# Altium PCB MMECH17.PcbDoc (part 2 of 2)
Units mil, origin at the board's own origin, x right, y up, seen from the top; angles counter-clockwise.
Board outline 2559.06 x 2205.16 mil, 4 copper layers (Top Layer, Ground Plane, Mid Layer 1, Bottom Layer), stack 56.756 mil thick; 96 components, 80 nets, 346 pads, 621 vias.

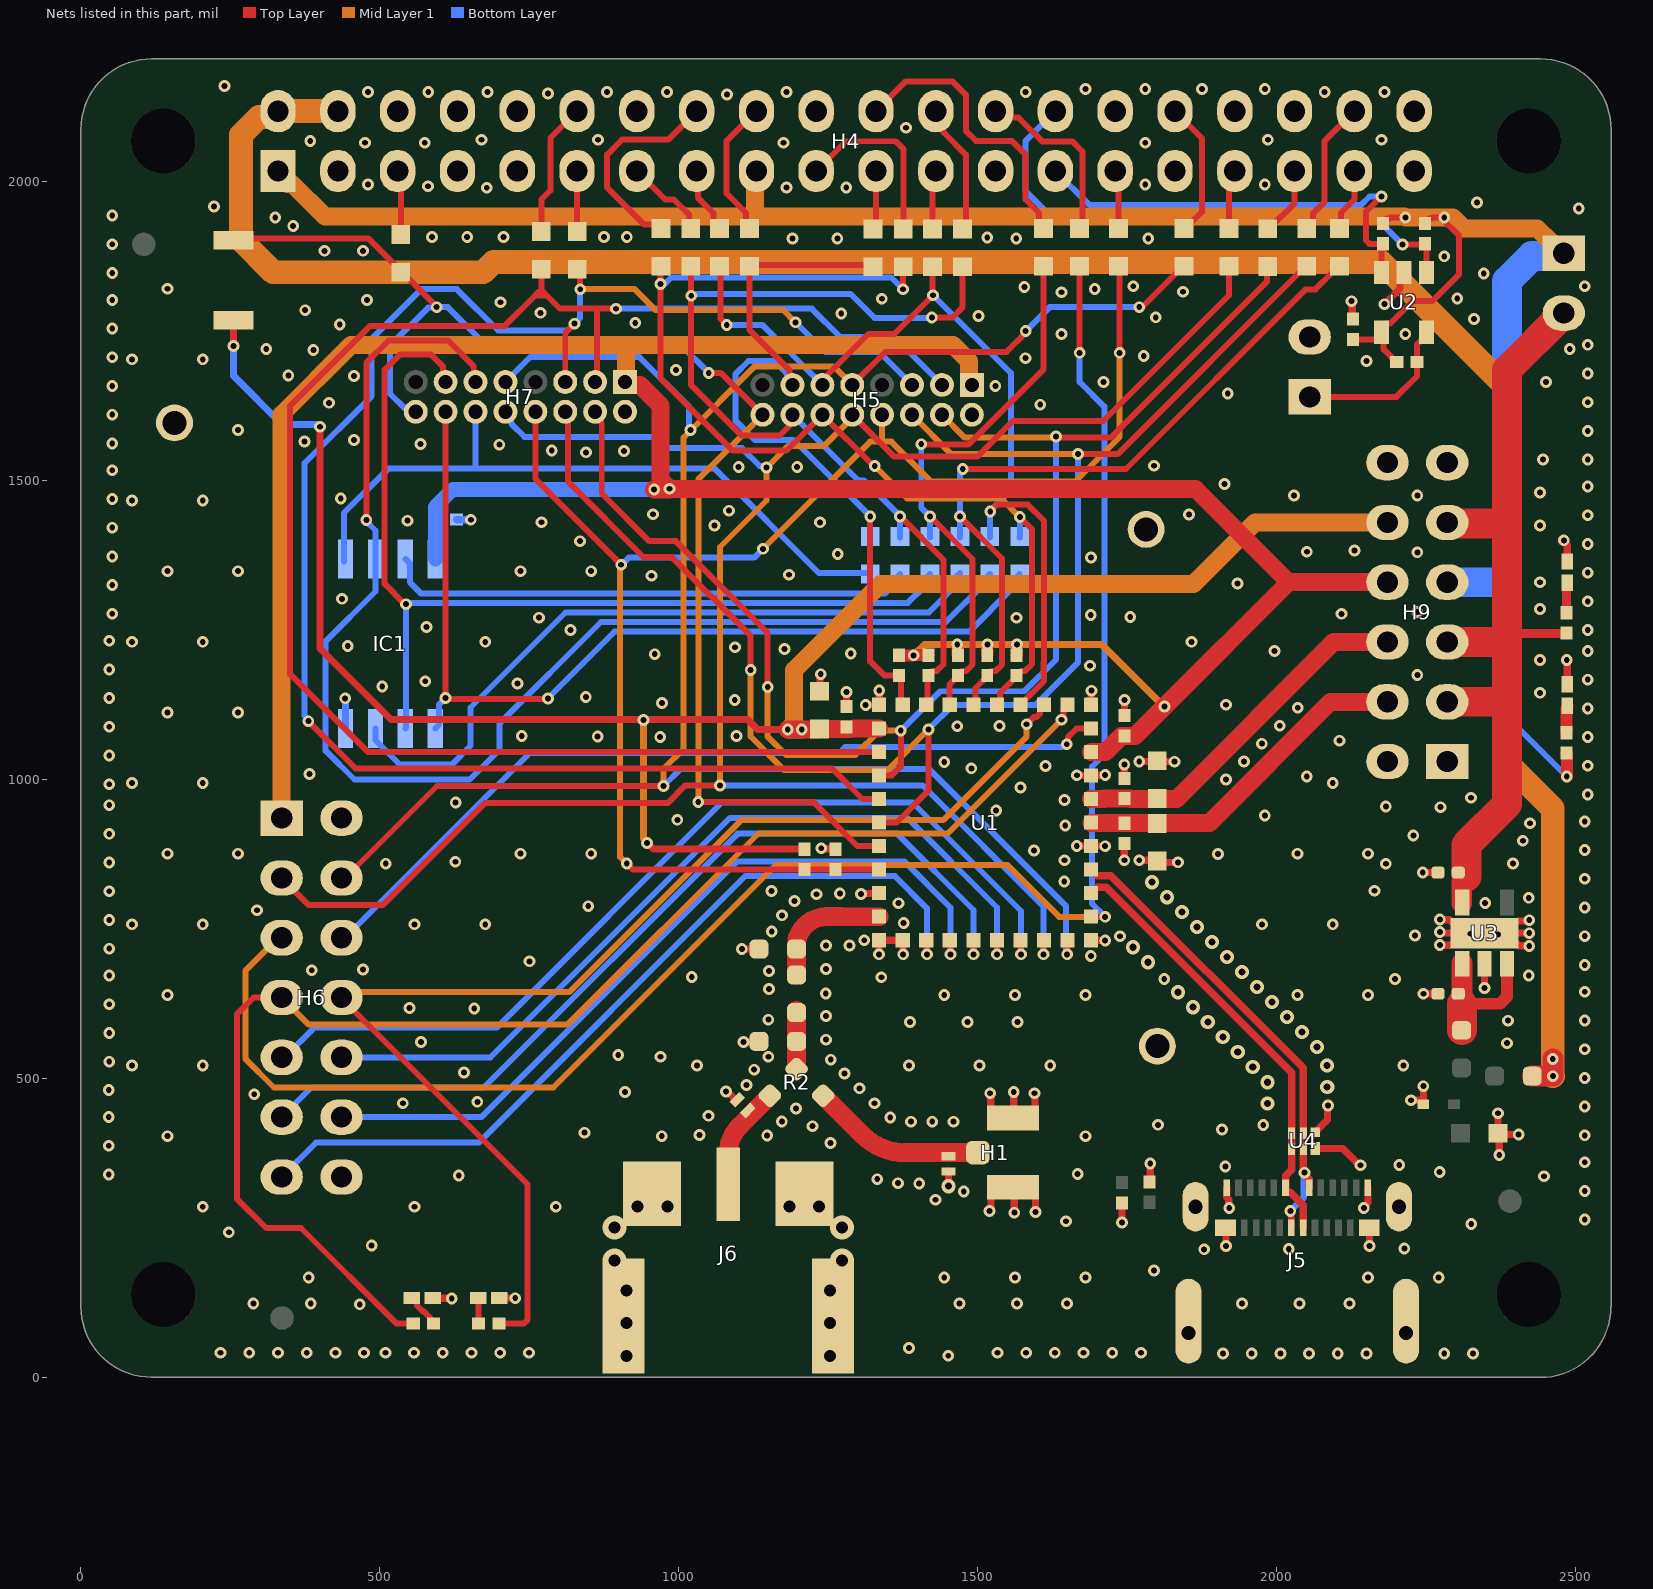
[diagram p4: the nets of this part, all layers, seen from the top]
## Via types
v1: diameter 19.68, hole 9.84, Top Layer to Bottom Layer, tented both sides, 584 vias
v2: diameter 23.62, hole 11.81, Top Layer to Bottom Layer, tented both sides, 25 vias
v3: diameter 40, hole 20, Top Layer to Bottom Layer, 12 vias

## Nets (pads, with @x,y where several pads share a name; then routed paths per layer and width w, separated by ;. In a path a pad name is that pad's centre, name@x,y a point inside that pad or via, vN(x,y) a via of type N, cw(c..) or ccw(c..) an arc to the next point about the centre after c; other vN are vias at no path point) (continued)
GND: C1.1 C2.2 C3.2 C4.2 C5.1 C6.2 C7.2 C8.2 C9.1 C10.2 C11.2 C12.2 C13.2 D1.1 D2.1 D3.K D4.K D5.K D6.K H1.2 H1.3 H3.2 H4.6 H4.9 H4.14 H4.20 H4.25 H4.30 H4.34 H4.39 H5.2 H6.2 H6.14 H7.2 H9.1 H9.2 H9.11 H9.12 IC1.4 J5.A1 J5.A12 J5.B1 J5.B12 J5.SH1 J5.SH2 J5.SH3 J5.SH4 J6.2 R3.1 R4.1 R45.2 R46.2 TP1.1 TP2.1 TP3.1 U1.1 U1.3 U1.11 U1.20 U1.23 U1.26 U1.30 U1.38 U2.2 U3.2 U3.6 U4.3 U4.4 VS1.A | length 1921.2
  Top Layer w12: D3.K@588.58,132.87 589.07,132.39 619.62,132.39 v1(620.11,131.9) ; D3.K@589.05,132.87 D3.K@589.17,132.76 ; D4.K@699.8,132.87 699.93,132.74 726.22,132.74 v1(726.35,132.61) ; v1(1078.74,478.35) 1080.82,478.35 1095.39,463.78 1096.65,463.78 D2.1@1097.44,464.57 ; v1(1105.32,716.54) R3.1@1133.86,716.54 ; v1(1108.27,561.02) 1108.76,561.52 1133.37,561.52 R4.1@1133.86,562.01 ; C4.2@1235.24,1147.64 1236.26,1148.66 1236.26,1175.24 v1(1237.28,1176.26) ; v1(1238.11,885) 1238.78,884.33 1261.05,884.33 C10.2@1261.72,883.66 ; C5.1@1279.53,1126.77 1279.97,1126.77 1280.2,1127 1280.2,1146.18 v1(1280.24,1146.22) ; v1(1304.51,808.73) 1305.15,809.37 1334.37,809.37 U1.3@1335,810 ; v1(1312.41,1124.59) 1312.49,1124.51 U1.11@1336.31,1124.51 ; v1(1334.86,707.64) 1334.93,707.71 1334.93,731.19 U1.1@1335,731.26 U1.38@1374.37,731.26 1374.76,730.86 1374.76,708.03 v1(1375.16,707.64) ; U1.11@1335,1124.96 U1.11@1335.08,1125.04 ; U1.11@1335,1125.12 U1.11@1335.08,1125.04 ; v1(1335.16,1148.94) 1335.08,1148.86 U1.11@1335.08,1125.04 ; U1.11@1336.23,1124.43 U1.11@1336.31,1124.51 ; U1.11@1336.39,1124.43 U1.11@1336.31,1124.51 ; D1.1@1449.8,345.47 D1.1@1450.79,344.49 v2(1450.79,319.88) ; v1(1519.68,278.54) 1521.91,280.77 1521.91,302.47 H1.3@1522.64,303.2 ; v1(1520.67,475.39) 1521.75,474.32 1521.75,448.72 1533.46,437.01 1559.06,437.01 H1.2@1559.06,434.06 ; H1.3@1558.07,312.99 1561.02,310.04 v1(1561.02,275.59) ; v1(1560.04,477.36) 1560.04,440.94 H1.2@1561.02,439.96 ; v1@1593.5,476.38 1595.73,474.15 1595.73,450.49 H1.2@1596.46,449.76 ; H1.3@1594.49,304.23 1595.38,304.23 1596.36,303.24 1596.36,276.67 v1(1596.46,276.57) ; v1(1665.49,888.87) 1665.57,888.79 U1.26@1689.38,888.79 ; v1(1665.57,1007.07) 1665.65,1006.99 U1.23@1689.47,1006.99 ; U1.30@1689.33,731.26 1689.48,731.11 1712.81,731.11 v1(1712.95,730.97) ; U1.26@1689.33,888.74 1689.4,888.67 1712.89,888.67 v1(1712.95,888.61) ; U1.23@1689.33,1006.85 U1.23@1689.47,1006.99 ; U1.20@1689.33,1124.96 1689.61,1125.24 1689.61,1148.31 v1(1689.88,1148.58) ; U1.23@1689.55,1006.91 U1.23@1689.47,1006.99 ; v1(1712.95,1007.39) 1712.68,1007.12 1689.6,1007.12 U1.23@1689.47,1006.99 ; v1(1741.14,259.06) R45.2@1741.14,291.73 ; v1(1745,865) C3.2@1745,892.68 ; C7.2@1745,1002.32 v1(1745,1025) ; C8.2@1745,1107 C8.2@1745,1107 1745.04,1132.83 v1(1745.08,1132.87) ; v1(1770,865) 1799.53,865 1800,865.47 1803.99,861.48 v1(1834.7,861.48) ; v1(1770,1030) 1799.53,1030 C6.2@1800,1029.53 ; R46.2@1788.39,325.39 v1(1788.39,358.07) ; C6.2@1799.92,1032.4 1800,1032.48 C6.2@1799.92,1032.56 ; C6.2@1804.92,1030.08 1805,1030 1828.82,1030 v1(1828.9,1029.92) ; J5.B12@1914.21,250.55 1915,249.76 v1(1915,220) ; J5.A1@1916.18,317.48 1916.18,300.92 1919.51,297.6 1919.51,284.31 v1(1920.55,283.26) ; U4.3@2063.98,382.78 2110.3,382.78 2138.18,354.9 v1(2140,354.9) ; U4.4@2064.29,410.14 2064.29,410.53 2084.65,430.89 2084.65,451.77 v1@2085.63,452.76 ; v1(2125,1800) 2126.25,1798.75 2126.25,1771.65 C9.1@2127.5,1770.4 ; v1(2145.55,283.26) 2145.55,285.34 2152.4,292.19 J5.A12@2152.4,317.48 ; J5.B1@2154.37,250.55 2155,249.92 v1(2155,220) ; v1(2180,1795) 2206,1821 2206,1841.58 U2.2@2212.5,1848.08 ; v1(2224.41,463.58) VS1.A@2245.08,463.58 ; v1@2244.18,844.46 C12.2@2269.38,844.46 ; 2245.08,466.54 v1(2245.08,487.2) ; v1(2245.08,641.73) C11.2@2269.42,641.73 ; v1(2272.64,723.43) 2273.14,722.93 2290.6,722.93 2294.05,726.38 U3.6@2294.29,726.38 ; v1(2272.64,745.08) 2274.11,743.61 2287.98,743.61 2288.48,743.11 U3.6@2294.29,743.11 ; v1(2272.64,765.75) 2272.97,765.42 2288.48,765.42 U3.6@2292.2,761.69 ; U3.2@2346.46,690.94 2347.44,689.96 v1(2347.44,651.57) ; C13.2@2370.08,411.42 v1(2370.08,441.93) ; v1(2372.05,372.05) C13.2@2372.05,402.56 ; C13.2@2374.02,406.5 v1(2404.53,406.5) ; U3.6@2398.62,743.11 v1(2422.24,743.11) ; U3.6@2402.68,724.53 2405.26,721.94 2421.76,721.94 v1(2422.24,721.46) ; U3.6@2403.3,762.31 2404.28,763.29 2420.77,763.29 v1(2422.24,764.76) ; v1(2480,1400) 2480,1397.92 2485.8,1392.12 D6.K@2485.8,1364.65 ; v1(2485,1200) 2485.8,1199.2 D5.K@2485.8,1158.98 ; v1(2490,1720) v1@2490.8,1719.2
  Bottom Layer w12: v1(441.93,1135.83) 442.29,1135.47 442.29,1085.98 IC1.4@442.65,1085.62 ; C1.1@628.54,1435.04 629.04,1434.55 v1(652.07,1434.55) v1@652.56,1434.06
  other v1: 1450.49,36.35 1910,40 1958,40 2006,40 2054,40 2102,40 2150,40 2280,40 2328,40 233.6,41.45 281.6,41.45 329.6,41.45 377.6,41.45 425.6,41.45 473.6,41.45 509.19,41.45 557.19,41.45 605.19,41.45 653.19,41.45 701.19,41.45 749.19,41.45 1532.81,41.45 1580.81,41.45 1628.81,41.45 1676.81,41.45 1724.81,41.45 1772.81,41.45 1384.84,49.21 466.32,122.31 288.35,123.93 384.35,123.93 1469.45,123.93 1565.45,123.93 1649.04,123.93 1941.89,123.93 2037.89,123.93 2121.49,123.93 380.91,167.32 1443.9,167.32 1562.01,167.32 1680.12,167.32 2152.56,167.32 2270.67,167.32 1794.76,179.13 1878.49,214.33 2020,215 2213.32,215.86 486.21,220.63 247.38,242.95 2325.18,256.62 1647.51,261.18 2515,264 203.74,285.43 558.07,285.43 794.29,285.43 1429.13,297.24 1476.38,311.02 2515,312 1401.92,324.19 1366.5,324.94 1331.7,331.62 2446.85,336.61 631.89,337.6 46.46,339.63 1666.96,340.27 2272.34,343.63 1913.9,353.05 2204.75,355.55 2515,360 46.46,387.63 1253.43,392.17 144.69,403.54 971.46,403.54 1680.12,403.54 1147.64,404.53 1034.57,405.42 2515,405 842.09,409.38 1908.32,414.75 1223.43,420.28 1801.25,422.5 1977.36,422.24 1388.25,427.78 1423.69,427.78 1459.12,427.78 1172.24,428.15 1353.49,434.66 46.46,435.63 1049.42,437.59 1195.87,449.8 2515,453 2085.63,454.72 538.39,458.66 1327.31,458.54 663,461.01 289.8,473.72 1594.62,475.27 909.97,477.26 46.46,480.63 1302.26,483.59 1113.19,489.17 2515,501 1277.1,508.54 640.75,509.84 1125.98,514.76 85.63,521.65 203.74,521.65 1030.51,521.65 1384.84,521.65 1502.95,521.65 1621.06,521.65 2211.61,521.65 47.33,528.18 1253.94,531.5 969.08,536.37 1149.61,536.42 898.6,539.53 2515,549 2384.84,559.06 568.9,561.02 1246.06,564.96 47.33,576.18 1386.78,594.4 1482.78,594.4 1566.37,594.4 2386.85,596.74 2515,597 1149.61,598.43 1246.06,604.33 549.47,617.84 657.85,617.14 47.33,624.18 144.69,639.76 1443.9,639.76 1562.01,639.76 1680.12,639.76 2034.45,639.76 2152.56,639.76 1245.72,642.2 2515,645 1150.59,649.61 1811.7,666.19 2197.83,666.34 1021.59,669.88 1338.58,669.29 47.33,672.18 2421.26,672.24 1150.71,679.83 385.98,681.07 471.8,682.22 1246.06,683.07 2515,690 750.2,695.95 1688.98,704.84 47.33,717.18 1246.06,722.44 1285.43,722.44 1310.04,731.3 1737.79,737.99 2515,738 2231.3,739.17 2370.08,741.14 2323.82,742.13 1155.29,745.69 85.63,757.87 203.74,757.87 558.07,757.87 676.18,757.87 1975.39,757.87 2093.5,757.87 1375.94,760.26 47.33,765.18 1172.55,772.92 294.4,781.29 2515,786 848.46,788.19 1367.46,793.2 2348.43,793.31 1193.26,796.69 2421.26,802.17 1230.32,808.07 1269.17,809.31 47.33,813.18 1155.14,813.36 2163.39,813.98 1644.58,829.59 2515,834 2244.15,844.42 509.84,859.25 2182.32,859.06 2394.96,859.46 47.33,861.18 626.16,862.5 1645.01,864.94 1901.78,875.42 144.69,875.98 262.8,875.98 735.24,875.98 853.35,875.98 2034.45,875.98 2152.56,875.98 1594.05,881.4 2515,882 2411.42,897.64 2228.35,906.5 47.33,909.18 1646.18,923.1 2423.47,926.82 2515,930 997.48,932.62 1980,940 1530.68,948.37 2273.62,953.74 2182.32,955.06 47.33,957.18 626.71,961.38 1644.98,965.62 2324.8,969.49 2520,975 1571.58,986.47 47.33,992.18 85.63,994.09 203.74,994.09 2093.5,994.09 1915,1000 2050,1005 382.44,1009.45 1489.17,1018.7 1613.19,1022.64 2520,1023 1443.9,1029.53 1945,1030 47.33,1040.18 1975,1060 2105,1065 864.17,1071.85 968.69,1071.22 2520,1071 737.2,1072.83 1096.46,1072.83 47.33,1088.18 1465.61,1089.04 1536.42,1089.57 2005,1090 144.69,1112.2 262.8,1112.2 2520,1119 2035,1120 1915,1125 971.77,1128.17 1093.5,1132.87 47.33,1136.18 844.4,1137.97 2440,1145 503.94,1155.51 730.04,1160.79 575.79,1164.37 2520,1167 2235,1175 47.33,1184.18 1687.51,1190.35 2440,1200 959.65,1209.65 1287.4,1210.63 1996.05,1214.77 2520,1215 1176.52,1218.3 1093.91,1221.27 446.3,1223.17 85.63,1230.31 203.74,1230.31 676.18,1230.31 1857.28,1230.31 47.33,1232.18 818.9,1250 2520,1250 577.76,1254.92 765.91,1270.69 1564.84,1270.6 1754.92,1271.65 1688.85,1275.1 52.33,1277.18 2108.16,1277.07 2235,1280 2440,1285 2520,1298 436.87,1302.2 52.33,1325.18 1934.06,1327.76 2440,1330 954.1,1340.74 1184.06,1342.52 2520,1346 144.69,1348.42 262.8,1348.42 735.24,1348.42 853.35,1348.42 1689.28,1371.26 52.33,1373.18 1265.75,1376.97 2050.2,1380.91 2235,1380 2129.92,1382.87 2520,1394 834.65,1398.67 52.33,1421.18 1059.69,1425 2440,1425 770.18,1430.2 1236.22,1430.12 546.04,1432.88 2520,1442 956.64,1443.64 1853.06,1443.31 1083.73,1449.65 85.63,1466.54 203.74,1466.54 52.33,1469.18 434.57,1469.95 2028.95,1475.12 2235,1475 2440,1480 2520,1490 1912.4,1494.09 52.33,1517.18 1100,1522.69 1197.83,1522.64 1794.54,1524.76 2445,1535 2520,1535 844.49,1547.24 908.46,1549.21 787.4,1550.2 699.8,1560.04 567.91,1561.02 52.33,1562.18 373.94,1565.5 456.51,1567.91 2520,1583 262.8,1584.65 52.33,1610.18 1604.33,1626.97 415,1630 2520,1631 1917.9,1645.76 52.33,1658.18 1529.3,1657.98 1710.14,1664.65 2450,1665 346.85,1675.52 456.51,1675 2520,1679 995,1685 2150,1700 85.63,1702.76 203.74,1702.76 1579.72,1704.72 52.33,1706.18 1777.43,1708.32 388.69,1718.29 310,1720 2520,1727 1639.76,1745.08 2215,1745 52.33,1754.18 432.86,1761.06 927.17,1763.78 2330,1770 1797.63,1772.95 1500.96,1775.05 1271.51,1779.42 768.7,1780.51 375,1785 701.77,1798.23 52.33,1802.18 478.42,1801.97 1339.45,1803.99 2301.83,1804.59 1640,1815 1842.92,1815.69 144.69,1820.87 1695.62,1820.34 1577.76,1823.82 1760,1825 2515,1825 2346.09,1846.25 52.33,1847.18 2280,1875 407.48,1884.16 471.84,1884.16 52.33,1895.18 1190,1905 1265,1905 1564.2,1905 1785,1905 1515.75,1906.5 586.94,1907.48 645.98,1907.48 706.66,1907.48 874.62,1907.48 912.98,1907.48 355,1925.84 325,1940 52.33,1943.18 2505,1955 222.36,1958.44 2335,1965 678.69,1989.65 1180,1990 1280,1990 580.32,1992.11 480,1995 1780,1995 1980,1995 475,2065 575,2065 1175,2065 1780,2065 383.52,2067.76 670,2070 865,2070 1985,2070 2175,2070 1380,2090 1080.33,2145.78 781.05,2147.49 480,2150 580.86,2150.02 680,2150 880,2150 980,2150 1180,2150 1580,2150 2080,2150 2180,2150 1680,2155 1780,2155 1875,2155 1980,2155 240,2160
  other v2: 1984.59,458.3 2084.31,486.06 1984.59,493.73 1959.78,519.03 2084.01,521.5 1934.72,544.08 2067.17,552.67 1909.67,569.14 2042.12,577.73 1884.62,594.19 2017.06,602.78 1859.56,619.24 1992.01,627.83 1834.51,644.3 1966.95,652.89 1941.9,677.94 1784.4,694.41 1916.84,703 1759.35,719.46 1891.79,728.05 1866.74,753.1 1841.68,778.16 1816.63,803.21 1791.57,828.27
  other v3: 912.68,35.83 1252.68,35.83 912.68,145.83 1252.68,145.83 892.68,195.83 1272.68,195.83 892.68,250.83 1272.68,250.83 930.68,285.83 980.68,285.83 1184.68,285.83 1234.68,285.83
LED_G: H6.7 R39.1 U1.19 | length 2339.5
  Top Layer w10: H6.7@335.8,635.41 288.95,635.41 260.83,607.28 260.83,299.21 310.04,250 368.11,250 527.56,90.55 R39.1@555.83,90.55 ; v1(1640,1100) 1640,1102.62 1643.15,1105.77 1643.15,1118.15 U1.19@1649.96,1124.96
  Mid Layer 1 w10: H6.7@335.8,635.41 381.2,590 813.43,590 1133.11,909.68 1449.68,909.68 v1(1640,1100)
LED_R: H6.8 R40.1 U1.18 | length 2105.7
  Top Layer w10: H6.8@440,630 747.19,322.81 747.19,96.6 741.14,90.55 R40.1@699.09,90.55 ; v1(1581.69,1092.52) 1593.5,1104.33 1597.92,1104.33 1603.78,1110.19 1603.78,1118.15 U1.18@1610.59,1124.96
  Mid Layer 1 w10: H6.8@435.8,635.41 445.18,644.79 471.88,644.79 472.09,645 817.24,645 1104.33,932.09 1442.09,932.09 1581.69,1071.69 v1(1581.69,1092.52)
MM_BUSY: H6.5 R29.1 U1.29 | length 3027.8
  Top Layer w10: R29.1@1670,1860.47 1670.28,1860.2 v1(1670.28,1713.58) ; U1.29@1689.33,770.63 1689.46,770.5 1712.83,770.5 v1(1712.95,770.38)
  Mid Layer 1 w10: H6.5@335.8,735.41 329.89,735.41 275,680.51 275,532.98 322.98,485 790.12,485 1162.4,857.28 1549.21,857.28 1636.12,770.38 v1(1712.95,770.38)
  Bottom Layer w10: v1(1670.28,1713.58) 1670.28,1664.81 1711.61,1623.47 1711.61,1042.32 1690.94,1021.65 1690.94,792.39 v1(1712.95,770.38)
MM_DBG_RX: H5.9 H6.4 H7.9 R30.1 U1.31 | length 3466.6
  Top Layer w10: H6.4@435.8,835.41 441.7,835.41 595.47,989.17 v1(974.41,989.17) ; H5.9@1290,1660 1345,1715 1547.62,1715 1580,1747.38 v1(1580,1750) ; v1(1649.36,707.64) 1649.66,707.94 1649.66,730.96 U1.31@1649.96,731.26 ; v1(1770,1790) 1771.85,1791.85 1776.38,1791.85 R30.1@1845,1860.47
  Mid Layer 1 w10: v1(974.41,989.17) 974.41,1017.72 1008.11,1051.41 1008.11,1571.95 1127.16,1691 1259,1691 H5.9@1290,1660
  Bottom Layer w10: H7.9@710,1665 751.69,1706.69 934.06,1706.69 1017.08,1623.67 1017.08,1587.25 v1(1019.68,1584.65) ; v1(974.41,989.17) 1002.61,1017.37 1418.65,1017.37 1647.84,788.18 1647.84,709.16 v1(1649.36,707.64) ; v1(1580,1750) 1620,1790 v1(1770,1790)
MM_DBG_TX: H5.10 H6.3 H7.10 R31.1 U1.32 | length 3612.9
  Top Layer w10: H6.3@335.8,835.41 381.2,790 505,790 675.63,960.63 981.3,960.63 1010.83,990.16 v1(1068.9,990.16) ; H5.10@1290,1610 1360,1540 1498.72,1540 1558.72,1600 1710.24,1600 1920,1809.76 R31.1@1920,1858.5 R31.1@1920,1860.47 ; v1(1609.62,707.64) 1610.1,708.13 1610.1,730.77 U1.32@1610.59,731.26
  Mid Layer 1 w10: v1(1068.9,990.16) 1068.9,1388.9 1146.65,1466.65 v1(1146.65,1521.65) 1183.07,1558.07 1243.11,1558.07 1290,1604.96 H5.10@1290,1610
  Bottom Layer w10: H7.10@710,1615 710,1606.88 719.73,1597.15 719.73,1595.23 741.95,1573.01 960.46,1573.01 979.33,1554.13 1105.31,1554.13 1135.19,1524.26 1144.05,1524.26 v1(1146.65,1521.65) ; v1(1068.9,990.16) 1407.48,990.16 1609.62,788.02 v1(1609.62,707.64)
MM_GPIO3: H6.6 U1.21 | length 1404.2
  Top Layer w10: v1(1648.62,1059.06) 1650.48,1060.91 1650.48,1070.48 1665.3,1085.3 1689.04,1085.3 U1.21@1689.33,1085.59
  Bottom Layer w10: H6.6@435.8,735.41 441.7,735.41 750.59,1044.29 1268.06,1044.29 1277.9,1054.13 1641.08,1054.13 1646,1059.06 v1(1648.62,1059.06)
MM_GPIO6: H6.9 U1.33 | length 1584.7
  Top Layer w10: U1.33@1571.22,731.26 1571.72,730.76 1571.72,708.13 v1(1572.21,707.64)
  Bottom Layer w10: H6.9@335.8,535.41 340.41,535.41 390,585 695.24,585 1071.85,961.61 1390.75,961.61 1572.21,780.15 v1(1572.21,707.64)
MM_GPIO7: H6.10 U1.34 | length 1426.3
  Top Layer w10: U1.34@1531.85,731.26 1531.94,731.17 1531.94,707.72 v1(1532.02,707.64)
  Bottom Layer w10: H6.10@435.8,535.41 685.01,535.41 1085.63,936.02 1381.89,936.02 1532.02,785.89 v1(1532.02,707.64)
MM_GPIO8: H6.11 U1.35 | length 1504.2
  Top Layer w10: U1.35@1492.48,731.26 1492.66,731.08 1492.66,707.82 v1(1492.84,707.64)
  Bottom Layer w10: H6.11@335.8,435.41 385.39,485 673.98,485 1098.43,909.45 1365.16,909.45 1492.84,781.77 v1(1492.84,707.64)
MM_GPIO9: H6.12 U1.36 | length 1331.5
  Top Layer w10: v1@1453.11,706.19 1453.71,706.79 1453.71,730.66 U1.36@1453.11,731.26
  Bottom Layer w10: H6.12@435.8,435.41 669.66,435.41 1097.44,863.19 1376.97,863.19 1454.32,785.84 v1(1454.32,707.64)
MM_GPIO10: H6.13 U1.37 | length 1411
  Top Layer w10: U1.37@1413.74,731.26 1414.27,730.73 1414.27,708.17 v1(1414.8,707.64)
  Bottom Layer w10: H6.13@335.8,335.41 393.11,392.72 665.35,392.72 1111.22,838.58 1361.22,838.58 1414.8,785.01 v1(1414.8,707.64)
MM_JTAG_TCK: H5.5 H7.5 R32.1 U1.7 | length 2928.2
  Top Layer w10: v1(380.37,1097.6) 459.26,1018.7 1255.91,1018.7 1307.13,967.48 U1.7@1335,967.48 ; H7.5@810,1665 810,1747.01 v1(825.36,1762.36) ; R32.1@830,1855.47 835,1850.47 v1(835,1820)
  Mid Layer 1 w10: v1(835,1820) 926.06,1820 960.63,1785.43 1174.06,1785.43 v1(1194.91,1764.59)
  Bottom Layer w10: v1(380.37,1097.6) 380.37,1100.22 374,1106.59 374,1529 486.22,1641.22 486.22,1737.2 569.02,1820 628.82,1820 697.83,1750.98 813.98,1750.98 v1(825.36,1762.36) 835,1772.01 v1(835,1820) ; v1(1194.91,1764.59) 1197.82,1761.68 1198.32,1761.68 1245,1715 1335,1715 H5.5@1390,1660
MM_JTAG_TDI: H5.3 H7.3 R34.1 U1.9 | length 2904
  Top Layer w10: R34.1@770,1855.47 R34.1@770,1853.5 770,1814.96 ; H7.3@860,1665 862.97,1667.97 862.97,1787.4 ; v1(894.68,1787.4) 862.97,1787.4 ; U1.9@1335,1046.22 479.86,1046.22 350,1176.08 350,1625 483.86,1758.86 708.86,1758.86 759.34,1809.34 ; 759.34,1809.34 777.09,1809.34 778.17,1810.41 ; 759.34,1809.34 764.96,1814.96 770,1814.96 ; 770,1814.96 773.62,1814.96 778.17,1810.41 ; 778.17,1810.41 801.18,1787.4 862.97,1787.4
  Bottom Layer w10: v1(894.68,1787.4) 1222.44,1787.4 1269.84,1740 1360,1740 H5.3@1440,1660
MM_JTAG_TDO: H5.4 H7.4 R35.1 U1.8 | length 2421
  Top Layer w10: H7.4@860,1615 860,1606.88 871.06,1595.82 871.06,1478.35 950.79,1398.62 995.08,1398.62 1148.62,1245.08 v1(1148.62,1154.53) ; U1.8@1335,1006.85 1356.26,1006.85 1371.18,1021.77 1371.18,1081.58 v1(1371.06,1081.69) ; v1(1630.91,1573.82) 1632.31,1572.41 1723,1572.41 1983.91,1833.32 1983.91,1859.13 R35.1@1984.96,1860.17
  Mid Layer 1 w10: v1(1148.62,1154.53) 1148.62,1071.85 1179.13,1041.34 1295.28,1041.34 1335.63,1081.69 v1(1371.06,1081.69) ; H5.4@1440,1610 1477.59,1572.41 1629.5,1572.41 v1(1630.91,1573.82)
  Bottom Layer w10: v1(1371.06,1081.69) 1437.01,1147.64 1577.76,1147.64 1630.91,1200.79 v1(1630.91,1573.82)
MM_JTAG_TMS: H5.6 H7.6 R33.1 U1.6 | length 2717.9
  Top Layer w10: H7.6@810,1615 814.96,1610.04 814.96,1498.03 940.94,1372.05 988.19,1372.05 1120.08,1240.16 v1(1120.08,1183.07) ; U1.6@1335,928.11 1364.13,928.11 1417.32,981.3 v1(1417.32,1083.66) ; v1(1667.32,1544.29) 1733.82,1544.29 R33.1@2050,1860.47
  Mid Layer 1 w10: v1(1120.08,1183.07) 1120.08,1071.86 1176.19,1015.75 1349.41,1015.75 v1(1417.32,1083.66) ; H5.6@1390,1610 1455.71,1544.29 v1(1667.32,1544.29)
  Bottom Layer w10: v1(1417.32,1083.66) 1458.66,1125 1596.8,1125 1667.32,1195.52 v1(1667.32,1544.29)
MM_RESET_N: C10.1 H5.8 H7.8 R36.2 R38.1 U1.4 | length 2552.1
  Top Layer w10: H7.8@760,1615 760,1502.8 v1(903.54,1359.25) ; v1(912.79,859.61) 913.22,859.61 923.49,849.34 R36.2@1210.06,849.34 ; R36.2@1215.8,849.37 U1.4@1335,849.37 ; R38.1@1735,1860.47 1737.2,1858.27 v1(1737.2,1713.58)
  Mid Layer 1 w10: v1(903.54,1359.25) 903.54,1356.63 901.57,1354.66 901.57,870.83 v1(912.79,859.61) ; v1(1140.75,1385.83) 1319.88,1564.96 1340.55,1564.96 ; H5.8@1340,1610 1340,1565.51 1340.55,1564.96 ; v1(1737.2,1713.58) 1737.2,1572.94 1662.58,1498.32 1421.96,1498.32 1355.32,1564.96 1340.55,1564.96
  Bottom Layer w10: v1(903.54,1359.25) 904.4,1359.25 916.21,1371.06 1125.98,1371.06 v1(1140.75,1385.83)
MM_SD_CLK: H5.11 R5.1 R16.1 R23.1 U1.17 | length 1513.4
  Top Layer w10: R5.1@1068.17,1860.47 1069.82,1858.82 1069.82,1770.7 1080,1760.52 v1(1080,1760) ; H5.11@1240,1660 1240,1668.12 1316.96,1745.07 1360.07,1745.07 v1(1425,1810) 1424.43,1810.57 R16.1@1424.43,1859.65 ; v1(1520.73,1448.41) 1532.03,1459.71 1583.59,1459.71 1611,1432.31 1611,1195.59 1610.06,1194.66 1610.06,1177.39 1611,1176.45 1611,1164.74 U1.17@1571.22,1124.96
  Bottom Layer w10: v1(1080,1760) 1140,1760 1180,1720 H5.11@1240,1660 ; v1(1425,1810) 1555.12,1679.88 1555.12,1484 1520.73,1449.61 v1(1520.73,1448.41) 1520,1447.69 R23.1@1520,1406.5 R23.1@1520,1404.53
MM_SD_CMD: H5.12 R6.1 R15.2 R17.1 R24.1 U1.16 | length 1779.1
  Top Layer w10: R6.1@970,1860.47 969.49,1859.96 v1(969.49,1828.74) 969.49,1670.51 1090,1550 1180,1550 H5.12@1240,1610 1325.64,1524.36 v1(1327.53,1524.36) ; v1(1375,1820) R17.1@1375,1859.31 ; U1.16@1531.85,1124.96 1536.89,1130 1536.89,1144.76 1564.96,1172.83 R15.2@1564.96,1173.94 1564.96,1174.41 1572.17,1181.61 1579.06,1181.61 1590.55,1193.11 1590.55,1418.53 v1(1570.21,1438.87)
  Mid Layer 1 w10: v1(1327.53,1524.36) 1381.9,1470 1539.08,1470 v1(1570.21,1438.87)
  Bottom Layer w10: v1(969.49,1828.74) 971.34,1830.59 978.19,1830.59 987.16,1839.57 1355.43,1839.57 v1(1375,1820) ; R24.1@1570,1404.53 1570.21,1404.74 v1(1570.21,1438.87)
MM_SD_D0: H5.13 R7.1 R14.2 R18.1 R25.1 U1.12 | length 1322.1
  Top Layer w10: R7.1@1115,1860.47 R18.1@1323.6,1860.47 ; R7.1@1117.9,1860.35 R7.1@1117.9,1858.38 1117.9,1752.1 1185.25,1684.75 1185.25,1664.75 H5.13@1190,1660 ; v1(1320,1440) 1320,1197.72 1344.09,1173.62 1368.11,1173.62 1371.24,1170.49 1371.24,1128.09 U1.12@1374.37,1124.96
  Bottom Layer w10: H5.13@1190,1660 1190,1668.12 1180.25,1677.87 1180.25,1679.75 1160,1700 1116.47,1700 1095,1678.53 1095,1599.88 1126.97,1567.91 1192.09,1567.91 v1(1320,1440) R25.1@1320,1406.5 R25.1@1320,1404.53
MM_SD_D1: R8.1 R13.2 R26.1 U1.14 | length 958.2
  Top Layer w10: v1(1405.36,1560.84) 1406.26,1559.94 1483.78,1559.94 1610,1686.16 R8.1@1610,1858.5 R8.1@1610,1860.47 ; v1(1420,1440) 1491.14,1368.86 1491.14,1192.12 1480.64,1181.61 1473.74,1181.61 1466.54,1174.41 R13.2@1466.54,1173.94 1466.54,1172.83 1453,1159.3 U1.14@1453,1125.07
  Bottom Layer w10: v1(1405.36,1560.84) 1405.36,1454.64 v1(1420,1440) R26.1@1420,1406.5 R26.1@1420,1404.53
MM_SD_D2: R9.1 R12.2 R27.1 U1.15 | length 1257.4
  Top Layer w10: v1(1470,1440) 1540.35,1369.65 1540.35,1192.12 1529.85,1181.61 1522.95,1181.61 1515.75,1174.41 R12.2@1515.75,1173.94 1515.75,1172.83 1496.06,1153.15 1496.06,1128.54 U1.15@1492.48,1124.96 ; v1(1474.79,1519.16) 1474.98,1519.35 1747.69,1519.35 2048.23,1819.88 2064.41,1819.88 2092.28,1847.76 2094.25,1847.76 R9.1@2105,1858.5 R9.1@2105,1860.47
  Bottom Layer w10: R27.1@1470,1404.53 R27.1@1470,1406.5 v1(1470,1440) 1470,1511.74 1474.79,1516.54 v1(1474.79,1519.16)
MM_SD_D3: H5.14 R10.1 R11.2 R19.1 R28.1 U1.13 | length 1624.1
  Top Layer w10: R10.1@1020,1854.88 1020,1809.72 v1(1020.67,1809.06) 1020.17,1808.56 1020.17,1770.98 1020,1770.81 1020,1660 1105,1575 1168.33,1575 1184.26,1590.93 1184.26,1604.26 H5.14@1190,1610 ; v1(1370,1440) 1442.53,1367.47 1442.53,1192.73 1431.42,1181.61 1424.53,1181.61 1417.32,1174.41 R11.2@1417.32,1173.94 1417.32,1173.62 1415.53,1171.83 1415.53,1126.75 U1.13@1413.74,1124.96 ; v1(1423.08,1772.74) 1457.74,1772.74 1474.67,1789.67 R19.1@1474.67,1864.67
  Bottom Layer w10: v1(1020.67,1809.06) 1022.52,1810.91 1029.37,1810.91 1030.47,1812.01 1287.4,1812.01 1327.55,1771.86 1422.2,1771.86 v1(1423.08,1772.74) ; H5.14@1190,1610 1300,1500 1310,1500 v1(1370,1440) R28.1@1370,1406.5 R28.1@1370,1404.53
MM_WAKE: H5.16 H7.16 R37.1 S1.1 U1.5 | length 2272.8
  Top Layer w10: S1.1@255,1905 480.47,1905 v1@595,1790.47 ; v1(1032.48,962.6) 1224.57,962.6 1298.43,888.74 U1.5@1335,888.74 ; v1(1050,1680) 1070,1680 H5.16@1140,1610
  Mid Layer 1 w10: v1(1032.48,962.6) 1032.48,1502.48 H5.16@1140,1610
  Bottom Layer w10: H7.16@560,1615 554.26,1620.74 541.66,1620.74 516.73,1645.67 516.73,1725.39 580.6,1789.26 594.26,1789.26 v1(595,1790) 613.54,1790 675.2,1728.35 1001.65,1728.35 v1(1050,1680)
NetD1_2: D1.2 H1.1 R2.C | length 293.7
  Top Layer w31.5: R2.C@1241.39,471.21 1307.32,405.27 ccw(c1378.04,475.98) 1378.04,375.98 H1.1@1500,375.98
NetD2_2: D2.2 J6.1 R2.B | length 174.4
  Top Layer w31.5: J6.1@1082.68,322.83 1082.68,368.5 1082.68,374.74 cw(c1147.58,374.69) 1101.69,420.58 1122.05,440.94 R2.B@1152.31,471.21
NetD3_A: D3.A R39.2 | length 61.5
  Top Layer w10: D3.A@553.15,132.87 557.09,132.87 561.93,128.03 561.93,120.35 570.73,111.55 572.5,111.55 583.66,100.39 583.66,96.72 583.83,96.55 583.83,95.55 588.83,90.55 R39.2@589.83,90.55
NetD4_A: D4.A R40.2 | length 45.1
  Top Layer w10: D4.A@664.37,132.87 664.73,132.52 664.73,90.91 R40.2@665.09,90.55 ; R40.2@664.76,90.55 R40.2@666.51,88.8
NetD5_A: D5.A R42.1 | length 45.6
  Top Layer w20: R42.1@2484.36,1078.58 2484.36,1118.48 2485.8,1119.92 D5.A@2485.8,1123.54
NetD6_A: D6.A R43.1 | length 50.6
  Top Layer w15: R43.1@2484.36,1279.25 2484.36,1327.77 D6.A@2485.8,1329.21
NetR1_1: R1.1 R3.2 U1.2 | length 214.5
  Top Layer w31.5: R1.1@1196.85,673.23 R3.2@1196.85,716.54 1196.85,725.73 cw(c1228.35,725.77) 1198.65,736.27 cw(c1247.38,718.96) 1247.38,770.67 1270.67,770.67 1270.71,770.63 U1.2@1335,770.63
NetR1_2: R1.2 R2.A R4.2 | length 98.4
  Top Layer w31.5: R2.A@1196.85,515.75 R4.2@1196.85,562.01 R1.2@1196.85,614.17
Pi_GPIO0: H4.27 R21.2 U2.3 | length 738.3
  Top Layer w10: U2.3@2175,1848.08 2175,1893.25 2177.5,1895.75 2155.11,1895.75 2149.25,1901.61 2149.25,1949.61 2174.64,1975 v1(2175,1975)
  Bottom Layer w10: H4.27@1629.72,2017.72 1686.47,1960.97 2140.97,1960.97 2155,1975 v1(2175,1975)
Pi_GPIO1: H4.28 R22.2 U2.1 | length 907.8
  Top Layer w10: v1(2210,1895) 2246.75,1895 2247.5,1895.75 2250,1893.25 U2.1@2250,1848.08
  Bottom Layer w10: H4.28@1629.72,2117.72 1580,2067.99 1580,1983.83 1626.69,1937.14 2167.86,1937.14 v1(2210,1895)
Pi_GPIO2: H4.3
Pi_GPIO3: H4.5 R37.2 | length 110.4
  Top Layer w10: H4.5@529.72,2017.72 535,2012.44 R37.2@535,1911.5 R37.2@535,1909.53
Pi_GPIO4: H4.7
Pi_GPIO5: H4.29 R38.2 | length 100.4
  Top Layer w10: H4.29@1729.72,2017.72 1735,2012.44 R38.2@1735,1921.5 R38.2@1735,1919.53
Pi_GPIO6: H4.31
Pi_GPIO7: H4.26 R29.2 | length 305.9
  Top Layer w10: H4.26@1529.72,2117.72 1540.38,2107.06 1567.94,2107.06 1607.63,2067.37 1657.63,2067.37 1675,2050 1675,1924.53 R29.2@1670,1919.53
Pi_GPIO8: H4.24 R19.2 | length 222.1
  Top Layer w10: H4.24@1429.72,2117.72 1429.72,2098.54 1442.94,2085.32 1442.94,2082.06 1480,2045 1480,1924.27 R19.2@1474.43,1918.7
Pi_GPIO9: H4.21 R18.2 | length 101.2
  Top Layer w10: R18.2@1324.43,1918.7 1329.72,1923.99 H4.21@1329.72,2017.72
Pi_GPIO10: H4.19 R17.2 | length 307.5
  Top Layer w10: H4.19@1229.72,2017.72 1279.47,2067.46 1362.54,2067.46 1375.34,2054.66 R17.2@1375.34,1920.67 R17.2@1375.34,1918.7
Pi_GPIO11: H4.23 R16.2 | length 101.2
  Top Layer w10: R16.2@1424.43,1918.7 R16.2@1424.43,1920.67 1424.43,2012.42 H4.23@1429.72,2017.72
Pi_GPIO12: H4.32 R30.2 | length 229.4
  Top Layer w10: H4.32@1829.72,2117.72 1875,2072.44 1875,1949.53 R30.2@1845,1919.53
Pi_GPIO13: H4.33 R31.2 | length 102.2
  Top Layer w10: R31.2@1920,1919.53 R31.2@1920,1921.5 1920,1988.81 1929.72,1998.54 H4.33@1929.72,2017.72
Pi_GPIO14: H4.8
Pi_GPIO15: H4.10
Pi_GPIO16: H4.36
Pi_GPIO17: H4.11 R32.2 | length 103.3
  Top Layer w10: H4.11@829.72,2017.72 830,2017.44 R32.2@830,1916.5 R32.2@830,1914.53
Pi_GPIO18: H4.12 R34.2 | length 227.9
  Top Layer w10: R34.2@770,1914.53 R34.2@770,1916.5 770,1970 785,1985 785,2072.99 H4.12@829.72,2117.72
Pi_GPIO19: H4.35 R35.2 | length 117
  Top Layer w10: R35.2@1984.96,1919.23 2029.72,1964 H4.35@2029.72,2017.72
Pi_GPIO20: H4.38 R33.2 | length 231.2
  Top Layer w10: R33.2@2050,1919.53 2060.81,1930.33 2060.81,1947.34 2080,1966.53 2080,2067.99 H4.38@2129.72,2117.72
Pi_GPIO21: H4.40
Pi_GPIO22: H4.15 R5.2 | length 114.1
  Top Layer w10: H4.15@1029.72,2017.72 1031.86,2015.58 1031.86,1973.14 1057.63,1947.37 1057.63,1930.07 R5.2@1068.17,1919.53
Pi_GPIO23: H4.16 R6.2 | length 354
  Top Layer w10: R6.2@970,1919.53 961.68,1927.84 942.16,1927.84 880,1990 880,2045 905,2070 982.01,2070 H4.16@1029.72,2117.72
Pi_GPIO24: H4.18 R7.2 | length 233.3
  Top Layer w10: R7.2@1115,1919.53 1112.63,1921.9 1112.63,1947.37 1080,1980 1080,2067.99 H4.18@1129.72,2117.72
Pi_GPIO25: H4.22 R8.2 | length 494.9
  Top Layer w10: H4.22@1329.72,2117.72 1379.72,2167.72 1457.28,2167.72 1480,2145 1480,2085 1496.93,2068.07 1556.93,2068.07 1580,2045 1580,1970 1602.63,1947.37 1602.63,1926.9 R8.2@1610,1919.53
Pi_GPIO26: H4.37 R9.2 | length 108.4
  Top Layer w10: R9.2@2105,1919.53 2106.96,1921.49 2106.96,1947.37 2129.72,1970.13 H4.37@2129.72,2017.72
Pi_GPIO27: H4.13 R10.2 | length 143.3
  Top Layer w10: H4.13@929.72,2017.72 977.36,1970.08 991.54,1970.08 1017.1,1944.52 1017.1,1924.4 R10.2@1020,1921.5 ; R10.2@1019.02,1920.51 R10.2@1020,1919.53
QSPI_CLK: H7.11 IC1.6 R23.2 | length 2232.5
  Top Layer w10: v1(477.35,1433.91) 477.35,1696.84 514.76,1734.25 614.17,1734.25 656.96,1691.46 656.96,1668.04 H7.11@660,1665
  Bottom Layer w10: v1(477.35,1433.91) 477.35,1431.86 492.65,1416.56 IC1.6@492.65,1369.08 492.65,1314.37 409.42,1231.14 409.42,1048.03 457.45,1000 650,1000 700.24,1050.24 700.24,1093.95 869.71,1263.42 1446.66,1263.42 1509.25,1326.01 1509.25,1332.76 R23.2@1520,1343.5
QSPI_CSB: H7.14 IC1.1 R24.2 | length 1590.8
  Top Layer w10: H7.14@610,1615 610,1136.32 611.32,1135 780.56,1135 v1(781.19,1135.63)
  Bottom Layer w10: IC1.1@592.65,1085.62 598.97,1091.94 598.97,1125.78 609.67,1136.48 v1(609.84,1136.48) ; v1(781.19,1135.63) 781.19,1136.19 892.42,1247.42 1485.6,1247.42 1559.49,1321.3 1559.49,1333 R24.2@1570,1343.5
QSPI_D0: H7.12 IC1.5 R25.2 | length 1158.9
  Bottom Layer w10: IC1.5@440,1365 440,1445.91 514.09,1520 660,1520 ; H7.12@660,1615 660,1520 ; R25.2@1320,1345.47 1234.25,1345.47 1059.72,1520 660,1520
QSPI_D1: H7.13 IC1.2 R26.2 | length 1663.7
  Top Layer w10: v1(543.6,1293.31) 541.69,1293.31 507.87,1327.13 507.87,1685.04 533.46,1710.63 585.63,1710.63 605.88,1690.38 605.88,1669.12 H7.13@610,1665
  Bottom Layer w10: IC1.2@542.65,1085.62 543.83,1086.79 543.83,1293.08 v1(543.6,1293.31) 545.45,1295.16 552.3,1295.16 552.56,1295.42 1383.01,1295.42 1409.25,1321.65 1409.25,1332.76 R26.2@1420,1343.5
QSPI_D2: IC1.3 R27.2 | length 1192.5
  Bottom Layer w10: IC1.3@492.65,1085.62 492.65,1065.93 533.58,1025 620,1025 651.57,1056.57 651.57,1120.48 810.51,1279.42 1418.2,1279.42 1459.25,1320.47 1459.25,1334.72 R27.2@1470,1345.47
QSPI_D3: IC1.7 R28.2 | length 887.2
  Bottom Layer w10: IC1.7@542.65,1369.08 550.03,1361.7 550.03,1329.97 568.58,1311.42 1344.88,1311.42 1359.25,1325.79 1359.25,1332.76 R28.2@1370,1343.5
RPI_ID_WP: H3.1 R20.2 U2.5 | length 274.9
  Top Layer w10: H3.1@2055,1640 2200,1640 2234.82,1674.82 2234.82,1727.72 2240.68,1733.58 2242.5,1733.58 2250,1741.08 U2.5@2250,1748.08
USB_D_N: J5.A7 J5.B7 U1.27 U4.2 U4.5 | length 799
  Top Layer w11.02: v1(2022.64,278.54) 2024.29,276.89 2024.29,270.76 2024.45,270.61 J5.B7@2024.45,250.55
  Top Layer w12.5: U1.27@1689.33,849.37 1699.52,839.19 1722.58,839.19 2043.95,517.82 2043.95,349.91 2044.89,348.97 2044.89,343.89 v1(2046.26,342.52) ; v1@2045.28,342.52 2045.28,340.39 2053.98,331.69 J5.A7@2053.98,317.48
  Bottom Layer w11.02: v1(2022.64,278.54) 2045.28,301.18 v1@2045.28,342.52
USB_D_P: J5.A6 J5.B6 U1.28 U4.1 U4.6 | length 748.6
  Top Layer w12.5: U1.28@1689.33,810 1699.52,820.19 1714.71,820.19 2024.95,509.95 2024.95,347.5 2024.61,347.16 2014.61,337.16 2014.61,309.99 2015,309.6 2022.48,309.6 2044.13,287.95 J5.B6@2044.13,250.55
VDD: C4.1 C5.2 H9.10 R36.1 S1.2 U1.10 | length 3325.8
  Top Layer w12: v1(255,1725) S1.2@255,1768.07 ; v1(400,1590) 400,1219.09 518.7,1100.39 1115.16,1100.39 1131.89,1083.66 v1(1182.09,1083.66) ; v1(946.85,893.7) 947.61,893.7 957.72,883.59 R36.1@1209.99,883.59
  Top Layer w30: v1(1182.09,1083.66) 1205.51,1083.66 v1(1205.56,1083.71) 1205.75,1083.9 1234.83,1083.9 1235.24,1084.3 1244.74,1084.3 1245.29,1084.86 C5.2@1285.05,1084.86 ; 1292.09,1085.59 U1.10@1335,1085.59
  Mid Layer 1 w12: v1(940.94,1099.41) 940.94,901.69 946.85,895.78 v1(946.85,893.7)
  Mid Layer 1 w30: v1(1205.56,1083.71) 1205.51,1083.66 v1(1182.09,1083.66) 1192.91,1094.49 1192.91,1182.91 1337.23,1327.23 1860.84,1327.23 1963.62,1430 H9.10@2185,1430
  Bottom Layer w12: v1(255,1725) 255,1675.12 336.28,1593.84 394.08,1593.84 397.92,1590 v1(400,1590)
VDD5: C11.1 R44.2 U3.1 U3.3 | length 248.6
  Top Layer w20: 2310.04,625 2373.23,625 2384.94,636.72 U3.3@2384.94,693.11
  Top Layer w35: U3.1@2309.94,693.11 2310.04,693.01 2310.04,625
  Top Layer w50: R44.2@2310.04,580.71 2310.04,625
VDD5_RPi: H4.2 H4.4 R41.1 | length 3834.3
  Top Layer w35: R41.1@2427.17,503.94 v1(2461.61,503.94) 2461.61,532.4 v1(2461.53,532.48)
  Mid Layer 1 w40: H4.4@429.72,2117.72 H4.2@329.72,2117.72 329.72,2116.97 320.92,2108.16 298.16,2108.16 267.72,2077.72 267.72,1902.28 321.69,1848.32 672.63,1848.32 689.92,1865.61 2174.39,1865.61 2385,1655 2385,1028.27 2461.53,951.74 v1(2461.53,532.48) 2461.53,504.02 v1(2461.61,503.94)
VDD_3V3: C12.1 H8.2 H9.3 H9.5 H9.9 R43.2 U3.5 | length 1445.4
  Top Layer w15: 2385,1247.64 2388.03,1244.61 R43.2@2484.36,1244.61
  Top Layer w30: U3.5@2309.32,793.73 U3.5@2309.94,793.11
  Top Layer w35: U3.5@2309.32,793.73 2309.32,829.72
  Top Layer w50: H9.3@2285,1130 2381.73,1130 2385,1133.27 ; H9.5@2285,1230 2385,1230 ; H9.9@2285,1430 2286.73,1428.27 2381.73,1428.27 2385,1425 ; 2316.93,890.75 2385,958.82 2385,1133.27 ; 2317.37,837.77 2317.37,885.5 ; H8.2@2480,1780 2385,1685 2385,1425 ; 2385,1133.27 2385,1230 ; 2385,1230 2385,1247.64 2385,1425
VDD_TX: C6.1 C7.1 H9.6 U1.24 | length 604.9
  Top Layer w30: U1.24@1689.33,967.48 1711.1,967.48 1711.95,968.33 1754.35,968.33 1755,967.68 1832.68,967.68 2095,1230 H9.6@2185,1230
VDD_USB: C2.1 C3.1 H9.4 U1.25 | length 578.8
  Top Layer w30: U1.25@1690.12,927.32 1800,927.32 1887.32,927.32 2090,1130 H9.4@2185,1130
VDDIO: C1.2 C8.1 H5.1 H6.1 H7.1 H9.8 IC1.8 R11.1 R12.1 R13.1 R14.1 R15.1 U1.22 | length 5009.8
  Top Layer w20: R14.1@1368.11,1208.27 1368.7,1207.68 v1(1392.72,1207.68) ; v1@1392.13,1208.27 R11.1@1417.32,1208.27 ; v1(1465.59,1225.98) 1465.59,1209.21 R13.1@1466.54,1208.27 ; R12.1@1515.75,1208.27 1516.21,1208.72 v1(1516.21,1225.98) ; R15.1@1564.96,1208.27 1565.52,1208.83 v1(1565.52,1225.98)
  Top Layer w30: H7.1@910,1665 915,1660 935,1660 969.49,1625.51 969.49,1500.98 v1(984.25,1486.22) ; v1(958.66,1485.24) 983.27,1485.24 v1(984.25,1486.22) ; U1.22@1689.33,1046.22 1713.54,1046.22 C8.1@1736.65,1069.33 ; C8.1@1740,1072.68 1762.64,1072.68 v1(1812.01,1122.05) 2019.96,1330 ; H9.8@2185,1330 2019.96,1330 ; v1(984.25,1486.22) 1863.74,1486.22 2019.96,1330
  Mid Layer 1 w12: v1(1392.72,1207.68) 1411.02,1225.98 v1(1465.59,1225.98) v1(1516.21,1225.98) v1(1565.52,1225.98) 1707.09,1225.98 1811.02,1122.05 v1(1812.01,1122.05)
  Mid Layer 1 w30: H6.1@335.8,935.41 335.8,1610.8 451.78,1726.78 911.82,1726.78 ; H7.1@910,1665 911.82,1666.82 911.82,1726.78 ; H5.1@1490,1660 1485,1665 1485,1700 1458.22,1726.78 911.82,1726.78
  Bottom Layer w25: IC1.8@592.95,1369.38 IC1.8@592.65,1369.08 592.65,1455.84 622.05,1485.24 v1(958.66,1485.24) 983.27,1485.24 v1(984.25,1486.22)
VDDIO_RPI: C9.2 H4.1 H4.17 H8.1 H9.7 R20.1 R21.1 R22.1 R42.2 U2.4 | length 3875.1
  Top Layer w10: C9.2@2127.5,1735.75 2167.5,1735.75 U2.4@2175,1743.25 ; R21.1@2177.5,1930.4 2177.5,1931.19 2184.7,1938.39 2188.95,1938.39 2190.56,1940 v1(2215,1940) ; R20.1@2200.18,1698.08 2199.39,1698.08 2192.18,1705.28 2192.18,1706.07 2178.82,1719.43 2178.82,1744.26 U2.4@2175,1748.08 2175,1755.08 2182.5,1762.58 2189.5,1762.58 2226.92,1800 2260,1800 2305,1845 2305,1909.3 v1@2279.68,1934.62 ; R22.1@2247.5,1930.4 2247.5,1931.19 2254.7,1938.39 2258.95,1938.39 2260.56,1940 v1(2280,1940)
  Top Layer w20: R42.2@2484.36,1043.94 2485,1043.29 v1(2485,1005)
  Mid Layer 1 w30: H4.1@329.72,2017.72 329.72,2011.81 345.47,1996.06 353.45,1996.06 408.1,1941.42 1126.98,1941.42 ; H4.17@1126.98,2017.72 1126.98,1941.42 ; v1@2213.58,1941.42 1126.98,1941.42 ; v1(2215,1940) v1(2280,1940) 2295,1940 2313.49,1921.51 2435.57,1921.51 2458.35,1898.73 2458.35,1895.75 2474.09,1880 H8.1@2480,1880
  Bottom Layer w10: 2385,1330 2385,1105 v1(2485,1005)
  Bottom Layer w50: H9.7@2285,1330 2385,1330 2385,1833.82 2426.65,1875.47 2475.47,1875.47 H8.1@2480,1880
pads on no net: FID1.1 FID2.1 FID3.1 H5.7 H5.15 H7.7 H7.15 J5.A2 J5.A3 J5.A8 J5.A10 J5.A11 J5.B2 J5.B3 J5.B8 J5.B10 J5.B11 MH1.1 MH2.1 MH3.1 MH4.1 U3.4

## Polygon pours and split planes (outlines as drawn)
GND on Mid Layer 1 "GND_L03_P001" (solid, remove dead copper, pour order 1): 0,118.54 0,2087.05 cw(c118.11,2087.05) 118.11,2205.16 2440.95,2205.16 cw(c2440.95,2087.05) 2559.06,2087.05 2559.06,118.54 2558.58,118.11 cw(c2440.47,118.11) 2440.47,0 118.54,0 118.11,0.43 cw(c118.11,118.54)
GND on Bottom Layer "GND_L04_P002" (solid, remove dead copper, pour order 2): 0,118.54 0,2087.05 cw(c118.11,2087.05) 118.11,2205.16 2440.95,2205.16 cw(c2440.95,2087.05) 2559.06,2087.05 2559.06,118.54 2558.58,118.11 cw(c2440.47,118.11) 2440.47,0 118.54,0 118.11,0.43 cw(c118.11,118.54)
GND on Top Layer "GND_L03_P004" (solid, remove dead copper, pour order 4): 0,118.54 0,2087.05 cw(c118.11,2087.05) 118.11,2205.16 2440.95,2205.16 cw(c2440.95,2087.05) 2559.06,2087.05 2559.06,118.54 2558.58,118.11 cw(c2440.47,118.11) 2440.47,0 118.54,0 118.11,0.43 cw(c118.11,118.54)
GND on Ground Plane (split plane): 2440.95,2185.06 2447.37,2185.06 2460.11,2183.38 2472.52,2180.06 2484.39,2175.14 2495.52,2168.72 2505.71,2160.9 2514.79,2151.81 2522.62,2141.62 2529.04,2130.49 2533.96,2118.62 2537.28,2106.21 2538.96,2093.47 2538.96,2087.05 2538.49,118.12 2538.49,118.11 2538.49,111.69 2536.81,98.95 2533.48,86.54 2528.57,74.67 2522.14,63.54 2514.32,53.35 2505.24,44.26 2495.04,36.44 2483.92,30.02 2472.05,25.1 2459.64,21.77 2446.9,20.1 2440.48,20.1 1243.13,20.32 1243.13,192.19 1245.34,193.37 1248.39,195.87 1253.93,201.41 1256.43,204.46 1257.29,206.07 1258.28,207.93 1261.28,215.16 1262.42,218.93 1262.81,222.85 1262.81,222.86 1262.81,230.69 1262.42,234.61 1261.38,238.04 1261.28,238.38 1258.28,245.61 1256.43,249.09 1253.93,252.13 1248.39,257.67 1245.35,260.17 1241.87,262.03 1234.64,265.02 1232.02,265.82 1230.87,266.17 1228.7,266.38 1226.95,266.55 1223.03,266.55 1110.24,266.55 1110.24,390.24 1115.72,401.07 1169.38,455.23 1136.33,488.28 1085.05,437.22 1074.08,423.8 1065.91,408.52 1055.36,388.78 1055.36,266.55 942.32,266.55 938.41,266.55 934.49,266.17 930.71,265.02 923.48,262.03 920.01,260.17 916.96,257.67 911.42,252.13 908.92,249.09 907.07,245.61 904.07,238.38 902.93,234.61 902.54,230.69 902.54,222.86 902.93,218.94 904.07,215.17 907.07,207.93 908.92,204.46 911.42,201.41 916.96,195.87 920.01,193.37 922.22,192.19 922.23,20.38 118.11,20.53 111.69,20.53 98.95,22.21 86.54,25.53 74.67,30.45 63.54,36.87 53.35,44.69 44.26,53.78 36.44,63.97 30.02,75.1 25.1,86.97 21.77,99.38 20.1,112.12 20.1,118.54 20.1,2087.05 20.1,2093.47 21.77,2106.21 25.1,2118.62 30.02,2130.49 36.44,2141.62 44.26,2151.81 53.35,2160.9 63.54,2168.72 74.67,2175.14 86.54,2180.06 98.95,2183.38 111.69,2185.06 118.11,2185.06

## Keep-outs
Keep-Out Layer:
  circle w7.87: c137.8,2067.8 r98
  circle w7.87: c137.8,138.66 r110.24
  circle w7.87: c2421.26,2067.8 r110.24
  circle w7.87: c2421.26,138.66 r110.24
  lines w10: 0,118.54 ccw(c118.11,118.54) 118.11,0.43 ; 0,2087.05 cw(c118.11,2087.05) 118.11,2205.16 ; 2440.95,0.43 ccw(c2440.95,118.54) 2559.06,118.54 ; 2440.95,2205.16 cw(c2440.95,2087.05) 2559.06,2087.05

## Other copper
Top Layer:
  pour cut-out: 1136.33,488.28 1173.33,524.56 1220.38,524.56 cw(c1220.38,522.86) 1221.59,524.06 1252.35,493.3 1219.3,460.25 1196.97,482.82 1169.38,455.23
  region net MM_JTAG_TDI: 862.97,1773.33 848.9,1787.4 878.83,1787.4
  pour cut-out: 1173.33,618.11 1173.48,618.26 1173.48,672.45 1220.22,672.45 1220.37,672.3 1220.37,618.11
  text ".Layer_Name" at 1327.31,-224.48 h60
Mid Layer 1:
  region net MM_RESET_N: 1340,1579.59 1325.37,1564.96 1355.32,1564.96
  region net VDDIO: 955.99,1726.78 926.01,1696.8 897.63,1696.8 867.65,1726.78
  region net VDDIO_RPI: 1082.81,1937.9 1112.79,1967.88 1141.16,1967.88 1171.14,1937.9
  text ".Layer_Name" at 1327.31,-224.48 h60
Bottom Layer:
  region net QSPI_D0: 644.9,1522.69 659.52,1537.31 660.27,1537.31 674.9,1522.69
  text ".Layer_Name" at 1327.31,-224.48 h60
Ground Plane (plane layer: these items are gaps in the copper):
  pour cut-out: 1136.33,488.28 1173.33,524.56 1220.38,524.56 cw(c1220.38,522.86) 1221.59,524.06 1252.35,493.3 1219.3,460.25 1219.3,460.48 1196.97,482.82 1169.38,455.23
  pour cut-out: 1252.35,493.3 1324.57,420.99 1335.37,412.13 1348.65,405.03 1363.05,400.66 1376.95,399.29 1479.73,399.51 1483.46,402 1490.16,403.33 1498.03,403.33 1521.65,402.56 1531.5,392.72 1531.5,357.53 1520.67,349.41 1498.03,348.64 1490.16,348.64 1483.46,349.97 1479.73,352.46 1377.44,352.58 1358.72,354.05 1339.89,358.58 1321.99,365.99 1305.47,376.11 1290.69,388.64 1219.3,460.25
  pour cut-out: 1136.33,488.28 1085.05,437.22 1074.08,423.8 1065.91,408.52 1055.36,388.78 1055.36,252.95 1110.24,252.95 1110.24,390.24 1115.72,401.07 1169.38,455.23
  pour cut-out: 1175.18,740.01 1177.3,745.84 1184.9,760.71 1194.24,772.09 1205.63,781.44 1218.62,788.38 1232.72,792.66 1247.38,794.19 1270.87,794.15 1335,794.15 1354.13,789.76 1358.52,770.63 1354.13,751.5 1335,747.11 1246.79,747.26 1240.03,746.37 1233.19,743.54 1227.31,739.03 1222.8,733.15 1220.83,728.39 1220.83,725.68 1173.33,725.68
  pour cut-out: 1173.33,524.56 1173.33,725.72 1220.83,725.72 1220.83,524.37 1173.33,524.37
  text ".Layer_Name" at 1327.31,-224.48 h60

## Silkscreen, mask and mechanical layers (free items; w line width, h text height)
Top Overlay:
  drawing of 9 lines, arcs and shapes, not listed
  text "2" at 245.08,2103.35 h40
  text "40" at 2287.4,2100.39 h40
  text "1" at 250,2006.89 h40
  text "39" at 2289.37,2003.94 h40
  text "WAKE" at 303.47,1934.2 h60 r270
  text "9" at 720.12,1927.81 h40
  text "19" at 1209,1922 h40
  text "VDDIO / RPI" at 2296.38,1836.26 h40
  text "SPI" at 1365.18,1794.39 h47.24
  text "SDIO" at 989.23,1791.65 h47.24
  text "3V3" at 2330.82,1747.18 h50
  text "FLASH / DEBUG" at 302.17,1565.47 h60
  text "MM8108 / DEBUG" at 1525.24,1561.02 h60
  text "GND" at 1946.85,1500.14 h60
  text "GND" at 110.24,1490.16 h50
  text "VDD" at 1944.88,1400.8 h60
  text "GND" at 1733.27,1315.94 h50
  text "VDDIO" at 1944.18,1300.14 h60
  text "VDD" at 2452.33,1245.57 h60 r90
  text "VDD TX" at 1881.89,1200.8 h60
  text "Morse Micro" at 105.75,1182.61 h98.43
  text "VDD USB" at 1872.05,1100.14 h60
  text "MMECH17 V4" at 82.54,1033.5 h90
  text "VDDIO" at 2442.29,1019.7 h60 r90
  text "GND" at 1944.88,999.6 h60
  text "VDDIO" at 104.67,920 h60
  text "GND" at 488.27,909.29 h60
  text "GPIO0" at 93.5,809.29 h60
  text "GPIO1" at 488.27,809.29 h60
  text "GPIO2" at 91.54,709.29 h60
  text "GPIO3" at 488.27,709.29 h60
  text "GPIO4" at 90.55,609.29 h60
  text "GPIO5" at 488.27,609.29 h60
  text "GPIO6" at 89.57,509.29 h60
  text "GPIO7" at 488.27,509.29 h60
  text "GND" at 1752.95,450.79 h50
  text "GPIO9" at 498.27,420 h60
  text "GPIO8" at 89.57,409.45 h60
  text "GND" at 488.27,309.29 h60
  text "GPIO10" at 73.82,305.14 h60
  text "USER LEDS" at 463.46,177.36 h60
  text ".Layer_Name" at 1327.31,-224.48 h60
Bottom Overlay:
  drawing of 28 lines, arcs and shapes, not listed
  text "QSPI" at 1495,1285 h47.24
  text "Morse Micro" at 2458.26,588.77 h98.43
  text "MMECH17 V4" at 2457.94,443.9 h90
  text ".Layer_Name" at 1312.55,-228.41 h60
Top Paste:
  text ".Layer_Name" at 1312.55,-228.41 h60
Bottom Paste:
  text ".Layer_Name" at 1312.55,-228.41 h60
Top Solder:
  text ".Layer_Name" at 1312.55,-228.41 h60
Bottom Solder:
  text ".Layer_Name" at 1312.55,-228.41 h60
Drill Guide:
  text ".Layer_Name" at 1312.55,-228.41 h60
Top Assembly:
  lines w3.94: 2077.76,367.13 2013.78,367.13 2013.78,425.2 2077.76,425.2 ; 2077.76,367.13 2077.76,367.13 ; 2077.76,367.13 2077.76,425.2 ; 2077.76,425.2 2077.76,425.2
  lines w10: 279.72,1968.08 2279.72,1968.08 2279.72,2172.45 279.71,2172.45 279.72,1968.08
Fab Notes:
  drawing of 11 lines, arcs and shapes, not listed
  text "NOTES: UNLESS OTHERWISE SPECIFIED0" at -2906.5,3046.74 h60
  text "1. SPECIFICATIONS/TOLERANCES:" at -2906.5,2976.74 h60
  text "A. FABRICATE PER IPC-6012, CLASS 2, USING PROVIDED DATA FILES XXXXXXXX.ZIP" at -2906.5,2906.74 h60
  text "B. ALL SPECIFICATIONS USED SHALL BE PER THEIR LATEST REVISIONS." at -2906.5,2836.74 h60
  text "C. THE DIMENSIONS OF CIRCUIT FEATURES IN THE PROVIDED DATA MAY BE ADJUSTED" at -2906.5,2766.74 h60
  text "ONLY TO COMPENSATE FOR PROCESS TOLERANCES; ADDING, REMOVING OR RELOCATING" at -2906.5,2696.74 h60
  text "CIRCUIT FEATURES IS NOT ALLOWED" at -2906.5,2626.74 h60
  text "D. REMOVE ALL BURRS AND BREAK SHARP EDGES, .381 [.015] MAX RADIUS." at -2906.5,2556.74 h60
  text "E. PARENTHETICAL INFORMATION IS FOR REFERENCE ONLY." at -2906.5,2486.74 h60
  text "F. REPAIR OF PCB DEFECTS IS NOT PERMITTED." at -2906.5,2416.74 h60
  text "2. DIELECTRIC MATERIAL:" at -2906.54,2276.74 h60
  text "A. DIELECTRIC MATERIAL SHALL BE PER IPC-4101/99, /124, /126 OR /129 (RoHS COMPLIANT EPOXY-GLASS)" at -2906.5,2206.74 h60
  text "B. MINIMUM DIELECTRIC THICKNESS SHALL BE .051 [.002] FOR REFERENCED STACK-UP" at -2906.5,2136.74 h60
  text "DIMENSIONS OF.076 [.003] OR GREATER; IPC-6012 REQUIREMENTS SHALL OTHERWISE" at -2906.5,2066.74 h60
  text "APPLY. SINGLE-PLY CONSTRUCTION IS ALLOWED." at -2906.5,1996.74 h60
  text "C. SEE LAYER STACK-UP FOR REQUIRED COPPER WEIGHTS AND THE FINISHED PCB" at -2906.5,1926.74 h60
  text "THICKNESS. IF SPECIFIED, 1/3 OZ. STARTING FOIL MAY BE ACHIEVED BY 1/2 OZ. FOIL REDUCTION." at -2906.5,1856.74 h60
  text "D. FINISHED PCB THICKNESS SHALL BE MEASURED OVER LANDS AND/OR" at -2906.5,1786.74 h60
  text "CONDUCTORS NOT COVERED BY SOLDER MASK. IF SPECIFIED, 1/3 OZ. STARTING FOIL" at -2906.5,1716.74 h60
  text "MAY BE ACHIEVED BY 1/2 OZ. FOIL REDUCTION." at -2906.5,1646.74 h60
  text "3. DRILLING:" at -2906.5,1506.74 h60
  text "A. VIA DIAMETERS SHALL BE VERIFIED BEFORE PLATING; ALL OTHER HOLE" at -2906.5,1436.74 h60
  text "DIAMETERS ARE FINISHED DIMENSIONS." at -2906.5,1366.74 h60
  text "B. LAYER-TO-LAYER MISREGISTRATION SHALL BE .127 [.005] MAXIMUM." at -2906.5,1296.74 h60
  text "4. SOLDER MASK:" at -2906.5,1156.74 h60
  text "A. APPLY LPI SOLDER MASK OVER BARE COPPER USING PROVIDED DATA." at -2906.5,1086.74 h60
  text "B. SOLDER MASK SHALL BE PER IPC-SM-840, CLASS T, COLOR PURPLE." at -2906.5,1016.74 h60
  text "C. THE DIMENSIONS OF SOLDER MASK-DEFINED PADS ON PLANES AND/OR WIDE" at -2906.5,946.74 h60
  text "CONDUCTORS SHALL NOT BE MODIFIED." at -2906.5,876.74 h60
  text "5. SILKSCREEN/MARKING:" at -2906.5,736.74 h60
  text "A. SILKSCREEN PCB PER PROVIDED DATA USING PERMANENT, NON-CONDUCTIVE" at -2906.5,666.74 h60
  text "INK, COLOR WHITE." at -2906.5,596.74 h60
  text "B. SUPPLIER ID AND TRACEABILITY INFORMATION SHALL NOT / BE APPLIED ON ANY PART OF THE PCB" at -2905.47,422.99 h60
  text "C. INK SHALL NOT BE APPLIED TO ANY SOLDERABLE SURFACE." at -2906.5,347.37 h60
  text "USING PROVIDED DATA." at -2906.5,277.37 h60
  text "6. ELECTRICAL TEST:" at -2906.5,137.37 h60
  text "A. DESIGN VERIFICATION SHALL BE DONE PRIOR TO PCB FABRICATION USING" at -2906.5,67.37 h60
  text "GERBER DATA AND AN IPC-D-356 NETLIST." at -2906.5,-2.63 h60
  text "B. ALL PCBS SHALL BE 100% ELECTRICALLY TESTED FOR OPENS AND SHORTS" at -2906.5,-72.63 h60
  text "C. APPLY TEST STAMP IN NON-LEGEND AREA ON SECONDARY SIDE OF PCB." at -2906.5,-142.63 h60
  text "Project:" at 2321.12,-188.98 h60
  text ".Project" at 2581.95,-201.39 h80
  text "7. FINAL FINISH:" at -2906.5,-277.63 h60
  text "Company:" at 2321.12,-279.53 h60
  text "Morse Micro" at 2582,-284.45 h80
  text "A. FINAL FINISH SHALL BE ELECTROLESS NICKEL/IMMERSION GOLD (ENIG) PER IPC-4552." at -2906.5,-351.66 h60
  text "Drawn By:" at 2321.12,-370.08 h60
  text ".DrawnBy" at 2581.95,-376.97 h80
  text "8. IMPEDANCE:" at -2909.96,-459.74 h60
  text "A. IMPEDANCE TOLERANCE SHALL BE +/- 10%." at -2909.96,-529.74 h60
  text "Date:" at 2321.12,-550.63 h60
  text "Rev:" at 3039.62,-554.57 h60
  text ".ModifiedDate" at 2508.06,-558.34 h80
  text ".Revision" at 3167.58,-561.46 h80
  text "B. SEE LAYER STACK-UP FOR IMPEDANCE REQUIREMENTS." at -2909.96,-599.74 h60
  text "9. IF PANELIZATION SPECIFICATIONS ARE PROVIDED, THE PCBS SHALL BE DELIVERED IN PANEL" at -2896.5,-722.63 h60
  text "FORM. HOWEVER, THESE SPECIFICATIONS MAY BE REPLACED BY SUPPLIER PREFERRED" at -2896.5,-792.63 h60
  text "(SPECIFICATIONS AS APPROVED)." at -2896.5,-862.63 h60
Board:
  lines w5: 942.32,0 942.32,207.09 cw(c942.32,226.77) 942.32,246.46 1223.03,246.46 cw(c1223.03,226.77) 1223.03,207.09 1223.03,0
  lines w10: 118.11,0.43 cw(c118.11,118.54) 0,118.54 0,2087.05 cw(c118.11,2087.05) 118.11,2205.16 2440.95,2205.16 cw(c2440.95,2087.05) 2559.06,2087.05 2559.06,118.54 ; 118.54,0 939.96,0 ; 1225.39,0 2438.09,0 ; 2440.47,0 ccw(c2440.47,118.11) 2558.58,118.11
Drill Drawing:
  text ".Layer_Name" at 1312.55,-228.41 h60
